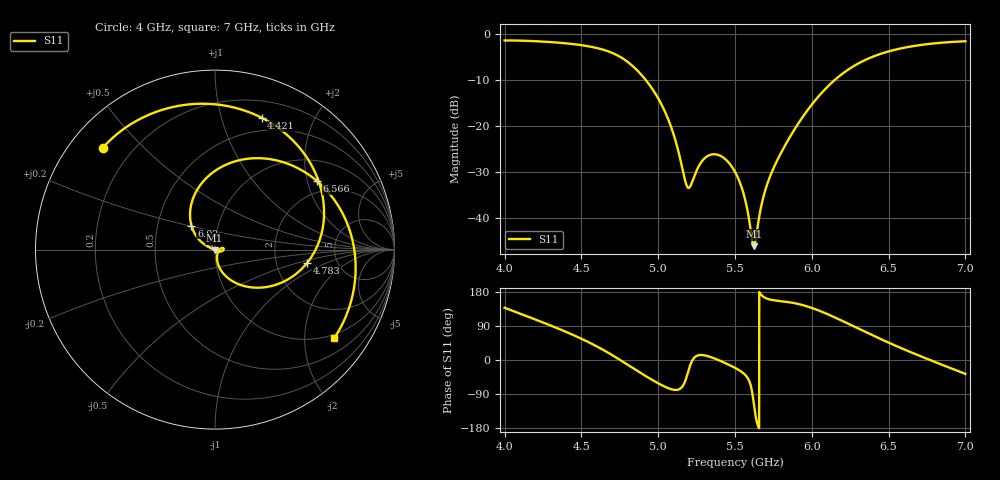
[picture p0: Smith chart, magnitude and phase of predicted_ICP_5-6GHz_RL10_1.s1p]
! ICP-predicted S11, target 5.000-6.000 GHz at -10 dB. Complex ensemble mean (passive and causal);
! its |S11| can differ slightly from the dB-domain mean reported in designs.csv.
!  Air_gap = 1.83mm
!  W_Patch = 13.09mm
!  L_Patch = 16.62mm
!  Sx = 0.46mm
!  Sy = 4.26mm
!  W_Patch1 = 14.22mm
!  WS = 1.29mm
!  Curve_Amp1 = 2.4mm
!  Extra = 3.09mm
# GHz S MA R 50
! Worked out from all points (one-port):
!   3001 points, 4 GHz to 7 GHz, reference 50 ohm
!   lowest |S11| = -46.1 dB at 5.623 GHz (marker M1), VSWR 1.01, Z = 49.8 - j0.438 ohm
!   |S11| at or under -10 dB: 4.918 GHz to 6.151 GHz (1.234 GHz wide, 22.3 % of centre)
!   S11 on the Smith chart (normalised r, x): 4 GHz: 0.10, +0.38; 4.421 GHz: 0.36, +1.35; 4.783 GHz: 3.03, -0.60; 6.02 GHz: 0.74, +0.21; 6.566 GHz: 1.59, +2.29; 7 GHz: 0.88, -2.77
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4  0.8438 137.8
4.196  0.8295 107.5
4.375  0.7928 78.5
4.421  0.7794 70.5
4.609  0.6935 34.0
4.75  0.563 0.5
4.783  0.5195 -8.0
4.88  0.3737 -32.9
4.989  0.2132 -59.0
5.065  0.1178 -74.3
5.125  0.05808 -78.6
5.196  0.02116 -29.6
5.279  0.03998 13.2
5.34  0.04844 8.0
5.422  0.0454 -5.4
5.5  0.03162 -20.7
5.559  0.01751 -36.4
5.623  0.00493 -116.9
5.678  0.01517 169.2
5.715  0.02463 161.0
5.875  0.08448 151.0
6.02  0.187 134.5
6.25  0.4211 93.3
6.409  0.5726 62.7
6.566  0.6843 34.1
6.625  0.7164 23.9
6.81  0.7887 -6.6
7  0.8277 -36.6
